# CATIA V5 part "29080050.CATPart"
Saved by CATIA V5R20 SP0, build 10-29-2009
Part number: 29080050
Definition: NONE
Nomenclature: 29080050
Source: Unknown
Description: 29080050
Bounding box of the stored display mesh (mm): x -25 to 44.548, y -54 to 88.548, z -44 to 44
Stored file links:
  C:\Users\Utente\Desktop\IO LAVORO\3D X SITO CF\X SITO\PLASTICA\RF1\29080050.CATPart

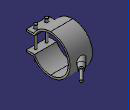
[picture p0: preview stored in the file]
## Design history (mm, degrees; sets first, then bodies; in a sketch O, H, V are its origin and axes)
Body1 "29080050" (main body)
  Solid1: solid without history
